VERSION 5.7 ;
BUSBITCHARS "[]" ;
DIVIDERCHAR "/" ;

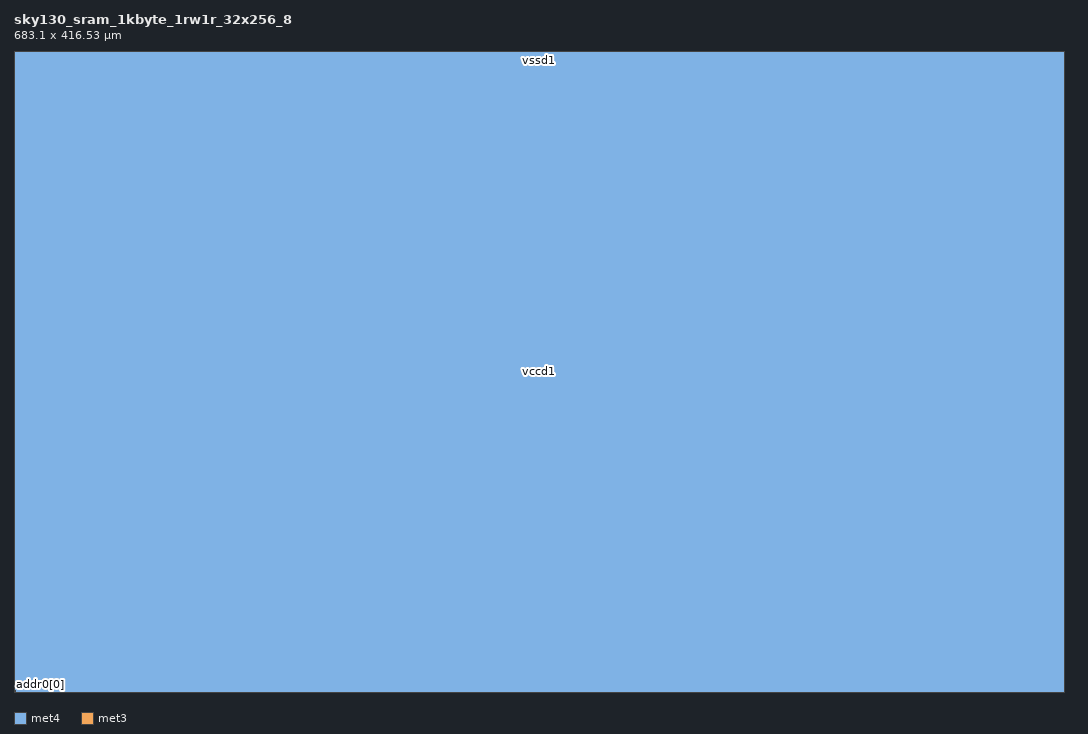
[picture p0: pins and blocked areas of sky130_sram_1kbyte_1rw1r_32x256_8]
MACRO sky130_sram_1kbyte_1rw1r_32x256_8
  CLASS BLOCK ;
  SIZE 683.100 BY 416.530 ;
  SYMMETRY X Y R90 ;
  
  PIN vccd1
    DIRECTION INOUT ;
    USE POWER ;
    PORT LAYER met4 ; RECT 0.000 0.000 683.100 416.530 ; END
  END vccd1
  
  PIN vssd1
    DIRECTION INOUT ;
    USE GROUND ;
    PORT LAYER met4 ; RECT 0.000 0.000 683.100 416.530 ; END
  END vssd1

  PIN clk0
    DIRECTION INPUT ;
    PORT LAYER met3 ; RECT 0 0 1 1 ; END
  END clk0
  PIN csb0
    DIRECTION INPUT ;
    PORT LAYER met3 ; RECT 0 0 1 1 ; END
  END csb0
  PIN web0
    DIRECTION INPUT ;
    PORT LAYER met3 ; RECT 0 0 1 1 ; END
  END web0

  PIN wmask0[3] DIRECTION INPUT ; PORT LAYER met3 ; RECT 0 0 1 1 ; END END wmask0[3]
  PIN wmask0[2] DIRECTION INPUT ; PORT LAYER met3 ; RECT 0 0 1 1 ; END END wmask0[2]
  PIN wmask0[1] DIRECTION INPUT ; PORT LAYER met3 ; RECT 0 0 1 1 ; END END wmask0[1]
  PIN wmask0[0] DIRECTION INPUT ; PORT LAYER met3 ; RECT 0 0 1 1 ; END END wmask0[0]

  PIN addr0[7] DIRECTION INPUT ; PORT LAYER met3 ; RECT 0 0 1 1 ; END END addr0[7]
  PIN addr0[6] DIRECTION INPUT ; PORT LAYER met3 ; RECT 0 0 1 1 ; END END addr0[6]
  PIN addr0[5] DIRECTION INPUT ; PORT LAYER met3 ; RECT 0 0 1 1 ; END END addr0[5]
  PIN addr0[4] DIRECTION INPUT ; PORT LAYER met3 ; RECT 0 0 1 1 ; END END addr0[4]
  PIN addr0[3] DIRECTION INPUT ; PORT LAYER met3 ; RECT 0 0 1 1 ; END END addr0[3]
  PIN addr0[2] DIRECTION INPUT ; PORT LAYER met3 ; RECT 0 0 1 1 ; END END addr0[2]
  PIN addr0[1] DIRECTION INPUT ; PORT LAYER met3 ; RECT 0 0 1 1 ; END END addr0[1]
  PIN addr0[0] DIRECTION INPUT ; PORT LAYER met3 ; RECT 0 0 1 1 ; END END addr0[0]

  PIN din0[31] DIRECTION INPUT ; PORT LAYER met3 ; RECT 0 0 1 1 ; END END din0[31]
  PIN din0[30] DIRECTION INPUT ; PORT LAYER met3 ; RECT 0 0 1 1 ; END END din0[30]
  PIN din0[29] DIRECTION INPUT ; PORT LAYER met3 ; RECT 0 0 1 1 ; END END din0[29]
  PIN din0[28] DIRECTION INPUT ; PORT LAYER met3 ; RECT 0 0 1 1 ; END END din0[28]
  PIN din0[27] DIRECTION INPUT ; PORT LAYER met3 ; RECT 0 0 1 1 ; END END din0[27]
  PIN din0[26] DIRECTION INPUT ; PORT LAYER met3 ; RECT 0 0 1 1 ; END END din0[26]
  PIN din0[25] DIRECTION INPUT ; PORT LAYER met3 ; RECT 0 0 1 1 ; END END din0[25]
  PIN din0[24] DIRECTION INPUT ; PORT LAYER met3 ; RECT 0 0 1 1 ; END END din0[24]
  PIN din0[23] DIRECTION INPUT ; PORT LAYER met3 ; RECT 0 0 1 1 ; END END din0[23]
  PIN din0[22] DIRECTION INPUT ; PORT LAYER met3 ; RECT 0 0 1 1 ; END END din0[22]
  PIN din0[21] DIRECTION INPUT ; PORT LAYER met3 ; RECT 0 0 1 1 ; END END din0[21]
  PIN din0[20] DIRECTION INPUT ; PORT LAYER met3 ; RECT 0 0 1 1 ; END END din0[20]
  PIN din0[19] DIRECTION INPUT ; PORT LAYER met3 ; RECT 0 0 1 1 ; END END din0[19]
  PIN din0[18] DIRECTION INPUT ; PORT LAYER met3 ; RECT 0 0 1 1 ; END END din0[18]
  PIN din0[17] DIRECTION INPUT ; PORT LAYER met3 ; RECT 0 0 1 1 ; END END din0[17]
  PIN din0[16] DIRECTION INPUT ; PORT LAYER met3 ; RECT 0 0 1 1 ; END END din0[16]
  PIN din0[15] DIRECTION INPUT ; PORT LAYER met3 ; RECT 0 0 1 1 ; END END din0[15]
  PIN din0[14] DIRECTION INPUT ; PORT LAYER met3 ; RECT 0 0 1 1 ; END END din0[14]
  PIN din0[13] DIRECTION INPUT ; PORT LAYER met3 ; RECT 0 0 1 1 ; END END din0[13]
  PIN din0[12] DIRECTION INPUT ; PORT LAYER met3 ; RECT 0 0 1 1 ; END END din0[12]
  PIN din0[11] DIRECTION INPUT ; PORT LAYER met3 ; RECT 0 0 1 1 ; END END din0[11]
  PIN din0[10] DIRECTION INPUT ; PORT LAYER met3 ; RECT 0 0 1 1 ; END END din0[10]
  PIN din0[9]  DIRECTION INPUT ; PORT LAYER met3 ; RECT 0 0 1 1 ; END END din0[9]
  PIN din0[8]  DIRECTION INPUT ; PORT LAYER met3 ; RECT 0 0 1 1 ; END END din0[8]
  PIN din0[7]  DIRECTION INPUT ; PORT LAYER met3 ; RECT 0 0 1 1 ; END END din0[7]
  PIN din0[6]  DIRECTION INPUT ; PORT LAYER met3 ; RECT 0 0 1 1 ; END END din0[6]
  PIN din0[5]  DIRECTION INPUT ; PORT LAYER met3 ; RECT 0 0 1 1 ; END END din0[5]
  PIN din0[4]  DIRECTION INPUT ; PORT LAYER met3 ; RECT 0 0 1 1 ; END END din0[4]
  PIN din0[3]  DIRECTION INPUT ; PORT LAYER met3 ; RECT 0 0 1 1 ; END END din0[3]
  PIN din0[2]  DIRECTION INPUT ; PORT LAYER met3 ; RECT 0 0 1 1 ; END END din0[2]
  PIN din0[1]  DIRECTION INPUT ; PORT LAYER met3 ; RECT 0 0 1 1 ; END END din0[1]
  PIN din0[0]  DIRECTION INPUT ; PORT LAYER met3 ; RECT 0 0 1 1 ; END END din0[0]

  PIN dout0[31] DIRECTION OUTPUT ; PORT LAYER met3 ; RECT 0 0 1 1 ; END END dout0[31]
  PIN dout0[30] DIRECTION OUTPUT ; PORT LAYER met3 ; RECT 0 0 1 1 ; END END dout0[30]
  PIN dout0[29] DIRECTION OUTPUT ; PORT LAYER met3 ; RECT 0 0 1 1 ; END END dout0[29]
  PIN dout0[28] DIRECTION OUTPUT ; PORT LAYER met3 ; RECT 0 0 1 1 ; END END dout0[28]
  PIN dout0[27] DIRECTION OUTPUT ; PORT LAYER met3 ; RECT 0 0 1 1 ; END END dout0[27]
  PIN dout0[26] DIRECTION OUTPUT ; PORT LAYER met3 ; RECT 0 0 1 1 ; END END dout0[26]
  PIN dout0[25] DIRECTION OUTPUT ; PORT LAYER met3 ; RECT 0 0 1 1 ; END END dout0[25]
  PIN dout0[24] DIRECTION OUTPUT ; PORT LAYER met3 ; RECT 0 0 1 1 ; END END dout0[24]
  PIN dout0[23] DIRECTION OUTPUT ; PORT LAYER met3 ; RECT 0 0 1 1 ; END END dout0[23]
  PIN dout0[22] DIRECTION OUTPUT ; PORT LAYER met3 ; RECT 0 0 1 1 ; END END dout0[22]
  PIN dout0[21] DIRECTION OUTPUT ; PORT LAYER met3 ; RECT 0 0 1 1 ; END END dout0[21]
  PIN dout0[20] DIRECTION OUTPUT ; PORT LAYER met3 ; RECT 0 0 1 1 ; END END dout0[20]
  PIN dout0[19] DIRECTION OUTPUT ; PORT LAYER met3 ; RECT 0 0 1 1 ; END END dout0[19]
  PIN dout0[18] DIRECTION OUTPUT ; PORT LAYER met3 ; RECT 0 0 1 1 ; END END dout0[18]
  PIN dout0[17] DIRECTION OUTPUT ; PORT LAYER met3 ; RECT 0 0 1 1 ; END END dout0[17]
  PIN dout0[16] DIRECTION OUTPUT ; PORT LAYER met3 ; RECT 0 0 1 1 ; END END dout0[16]
  PIN dout0[15] DIRECTION OUTPUT ; PORT LAYER met3 ; RECT 0 0 1 1 ; END END dout0[15]
  PIN dout0[14] DIRECTION OUTPUT ; PORT LAYER met3 ; RECT 0 0 1 1 ; END END dout0[14]
  PIN dout0[13] DIRECTION OUTPUT ; PORT LAYER met3 ; RECT 0 0 1 1 ; END END dout0[13]
  PIN dout0[12] DIRECTION OUTPUT ; PORT LAYER met3 ; RECT 0 0 1 1 ; END END dout0[12]
  PIN dout0[11] DIRECTION OUTPUT ; PORT LAYER met3 ; RECT 0 0 1 1 ; END END dout0[11]
  PIN dout0[10] DIRECTION OUTPUT ; PORT LAYER met3 ; RECT 0 0 1 1 ; END END dout0[10]
  PIN dout0[9]  DIRECTION OUTPUT ; PORT LAYER met3 ; RECT 0 0 1 1 ; END END dout0[9]
  PIN dout0[8]  DIRECTION OUTPUT ; PORT LAYER met3 ; RECT 0 0 1 1 ; END END dout0[8]
  PIN dout0[7]  DIRECTION OUTPUT ; PORT LAYER met3 ; RECT 0 0 1 1 ; END END dout0[7]
  PIN dout0[6]  DIRECTION OUTPUT ; PORT LAYER met3 ; RECT 0 0 1 1 ; END END dout0[6]
  PIN dout0[5]  DIRECTION OUTPUT ; PORT LAYER met3 ; RECT 0 0 1 1 ; END END dout0[5]
  PIN dout0[4]  DIRECTION OUTPUT ; PORT LAYER met3 ; RECT 0 0 1 1 ; END END dout0[4]
  PIN dout0[3]  DIRECTION OUTPUT ; PORT LAYER met3 ; RECT 0 0 1 1 ; END END dout0[3]
  PIN dout0[2]  DIRECTION OUTPUT ; PORT LAYER met3 ; RECT 0 0 1 1 ; END END dout0[2]
  PIN dout0[1]  DIRECTION OUTPUT ; PORT LAYER met3 ; RECT 0 0 1 1 ; END END dout0[1]
  PIN dout0[0]  DIRECTION OUTPUT ; PORT LAYER met3 ; RECT 0 0 1 1 ; END END dout0[0]

  PIN clk1 DIRECTION INPUT ; PORT LAYER met3 ; RECT 0 0 1 1 ; END END clk1
  PIN csb1 DIRECTION INPUT ; PORT LAYER met3 ; RECT 0 0 1 1 ; END END csb1

  PIN addr1[7] DIRECTION INPUT ; PORT LAYER met3 ; RECT 0 0 1 1 ; END END addr1[7]
  PIN addr1[6] DIRECTION INPUT ; PORT LAYER met3 ; RECT 0 0 1 1 ; END END addr1[6]
  PIN addr1[5] DIRECTION INPUT ; PORT LAYER met3 ; RECT 0 0 1 1 ; END END addr1[5]
  PIN addr1[4] DIRECTION INPUT ; PORT LAYER met3 ; RECT 0 0 1 1 ; END END addr1[4]
  PIN addr1[3] DIRECTION INPUT ; PORT LAYER met3 ; RECT 0 0 1 1 ; END END addr1[3]
  PIN addr1[2] DIRECTION INPUT ; PORT LAYER met3 ; RECT 0 0 1 1 ; END END addr1[2]
  PIN addr1[1] DIRECTION INPUT ; PORT LAYER met3 ; RECT 0 0 1 1 ; END END addr1[1]
  PIN addr1[0] DIRECTION INPUT ; PORT LAYER met3 ; RECT 0 0 1 1 ; END END addr1[0]

  PIN dout1[31] DIRECTION OUTPUT ; PORT LAYER met3 ; RECT 0 0 1 1 ; END END dout1[31]
  PIN dout1[30] DIRECTION OUTPUT ; PORT LAYER met3 ; RECT 0 0 1 1 ; END END dout1[30]
  PIN dout1[29] DIRECTION OUTPUT ; PORT LAYER met3 ; RECT 0 0 1 1 ; END END dout1[29]
  PIN dout1[28] DIRECTION OUTPUT ; PORT LAYER met3 ; RECT 0 0 1 1 ; END END dout1[28]
  PIN dout1[27] DIRECTION OUTPUT ; PORT LAYER met3 ; RECT 0 0 1 1 ; END END dout1[27]
  PIN dout1[26] DIRECTION OUTPUT ; PORT LAYER met3 ; RECT 0 0 1 1 ; END END dout1[26]
  PIN dout1[25] DIRECTION OUTPUT ; PORT LAYER met3 ; RECT 0 0 1 1 ; END END dout1[25]
  PIN dout1[24] DIRECTION OUTPUT ; PORT LAYER met3 ; RECT 0 0 1 1 ; END END dout1[24]
  PIN dout1[23] DIRECTION OUTPUT ; PORT LAYER met3 ; RECT 0 0 1 1 ; END END dout1[23]
  PIN dout1[22] DIRECTION OUTPUT ; PORT LAYER met3 ; RECT 0 0 1 1 ; END END dout1[22]
  PIN dout1[21] DIRECTION OUTPUT ; PORT LAYER met3 ; RECT 0 0 1 1 ; END END dout1[21]
  PIN dout1[20] DIRECTION OUTPUT ; PORT LAYER met3 ; RECT 0 0 1 1 ; END END dout1[20]
  PIN dout1[19] DIRECTION OUTPUT ; PORT LAYER met3 ; RECT 0 0 1 1 ; END END dout1[19]
  PIN dout1[18] DIRECTION OUTPUT ; PORT LAYER met3 ; RECT 0 0 1 1 ; END END dout1[18]
  PIN dout1[17] DIRECTION OUTPUT ; PORT LAYER met3 ; RECT 0 0 1 1 ; END END dout1[17]
  PIN dout1[16] DIRECTION OUTPUT ; PORT LAYER met3 ; RECT 0 0 1 1 ; END END dout1[16]
  PIN dout1[15] DIRECTION OUTPUT ; PORT LAYER met3 ; RECT 0 0 1 1 ; END END dout1[15]
  PIN dout1[14] DIRECTION OUTPUT ; PORT LAYER met3 ; RECT 0 0 1 1 ; END END dout1[14]
  PIN dout1[13] DIRECTION OUTPUT ; PORT LAYER met3 ; RECT 0 0 1 1 ; END END dout1[13]
  PIN dout1[12] DIRECTION OUTPUT ; PORT LAYER met3 ; RECT 0 0 1 1 ; END END dout1[12]
  PIN dout1[11] DIRECTION OUTPUT ; PORT LAYER met3 ; RECT 0 0 1 1 ; END END dout1[11]
  PIN dout1[10] DIRECTION OUTPUT ; PORT LAYER met3 ; RECT 0 0 1 1 ; END END dout1[10]
  PIN dout1[9]  DIRECTION OUTPUT ; PORT LAYER met3 ; RECT 0 0 1 1 ; END END dout1[9]
  PIN dout1[8]  DIRECTION OUTPUT ; PORT LAYER met3 ; RECT 0 0 1 1 ; END END dout1[8]
  PIN dout1[7]  DIRECTION OUTPUT ; PORT LAYER met3 ; RECT 0 0 1 1 ; END END dout1[7]
  PIN dout1[6]  DIRECTION OUTPUT ; PORT LAYER met3 ; RECT 0 0 1 1 ; END END dout1[6]
  PIN dout1[5]  DIRECTION OUTPUT ; PORT LAYER met3 ; RECT 0 0 1 1 ; END END dout1[5]
  PIN dout1[4]  DIRECTION OUTPUT ; PORT LAYER met3 ; RECT 0 0 1 1 ; END END dout1[4]
  PIN dout1[3]  DIRECTION OUTPUT ; PORT LAYER met3 ; RECT 0 0 1 1 ; END END dout1[3]
  PIN dout1[2]  DIRECTION OUTPUT ; PORT LAYER met3 ; RECT 0 0 1 1 ; END END dout1[2]
  PIN dout1[1]  DIRECTION OUTPUT ; PORT LAYER met3 ; RECT 0 0 1 1 ; END END dout1[1]
  PIN dout1[0]  DIRECTION OUTPUT ; PORT LAYER met3 ; RECT 0 0 1 1 ; END END dout1[0]

END sky130_sram_1kbyte_1rw1r_32x256_8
